VERSION 5.8 ;
BUSBITCHARS "[]" ;
DIVIDERCHAR "/" ;
UNITS
    DATABASE MICRONS 1000 ;
END UNITS

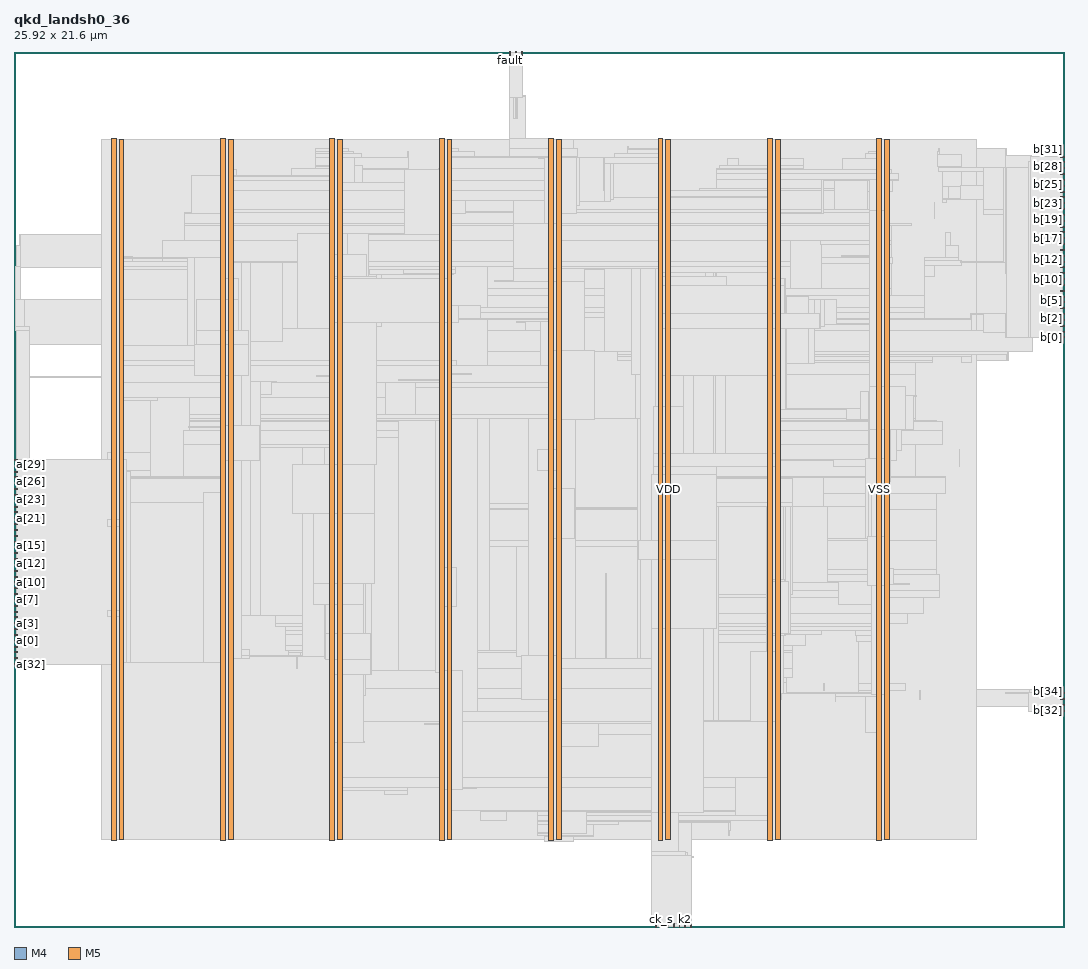
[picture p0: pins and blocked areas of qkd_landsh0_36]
MACRO qkd_landsh0_36
  FOREIGN qkd_landsh0_36 0 0 ;
  CLASS BLOCK ;
  SIZE 25.92 BY 21.6 ;
  PIN a[0]
    DIRECTION INPUT ;
    USE SIGNAL ;
    PORT
      LAYER M4 ;
        RECT  0 7.056 0.084 7.08 ;
    END
  END a[0]
  PIN a[10]
    DIRECTION INPUT ;
    USE SIGNAL ;
    PORT
      LAYER M4 ;
        RECT  0 8.496 0.084 8.52 ;
    END
  END a[10]
  PIN a[11]
    DIRECTION INPUT ;
    USE SIGNAL ;
    PORT
      LAYER M4 ;
        RECT  0 8.64 0.084 8.664 ;
    END
  END a[11]
  PIN a[12]
    DIRECTION INPUT ;
    USE SIGNAL ;
    PORT
      LAYER M4 ;
        RECT  0 8.784 0.084 8.808 ;
    END
  END a[12]
  PIN a[13]
    DIRECTION INPUT ;
    USE SIGNAL ;
    PORT
      LAYER M4 ;
        RECT  0 8.928 0.084 8.952 ;
    END
  END a[13]
  PIN a[14]
    DIRECTION INPUT ;
    USE SIGNAL ;
    PORT
      LAYER M4 ;
        RECT  0 9.072 0.084 9.096 ;
    END
  END a[14]
  PIN a[15]
    DIRECTION INPUT ;
    USE SIGNAL ;
    PORT
      LAYER M4 ;
        RECT  0 9.216 0.084 9.24 ;
    END
  END a[15]
  PIN a[16]
    DIRECTION INPUT ;
    USE SIGNAL ;
    PORT
      LAYER M4 ;
        RECT  0 9.36 0.084 9.384 ;
    END
  END a[16]
  PIN a[17]
    DIRECTION INPUT ;
    USE SIGNAL ;
    PORT
      LAYER M4 ;
        RECT  0 9.504 0.084 9.528 ;
    END
  END a[17]
  PIN a[18]
    DIRECTION INPUT ;
    USE SIGNAL ;
    PORT
      LAYER M4 ;
        RECT  0 9.648 0.084 9.672 ;
    END
  END a[18]
  PIN a[19]
    DIRECTION INPUT ;
    USE SIGNAL ;
    PORT
      LAYER M4 ;
        RECT  0 9.792 0.084 9.816 ;
    END
  END a[19]
  PIN a[1]
    DIRECTION INPUT ;
    USE SIGNAL ;
    PORT
      LAYER M4 ;
        RECT  0 7.2 0.084 7.224 ;
    END
  END a[1]
  PIN a[20]
    DIRECTION INPUT ;
    USE SIGNAL ;
    PORT
      LAYER M4 ;
        RECT  0 9.936 0.084 9.96 ;
    END
  END a[20]
  PIN a[21]
    DIRECTION INPUT ;
    USE SIGNAL ;
    PORT
      LAYER M4 ;
        RECT  0 10.08 0.084 10.104 ;
    END
  END a[21]
  PIN a[22]
    DIRECTION INPUT ;
    USE SIGNAL ;
    PORT
      LAYER M4 ;
        RECT  0 10.224 0.084 10.248 ;
    END
  END a[22]
  PIN a[23]
    DIRECTION INPUT ;
    USE SIGNAL ;
    PORT
      LAYER M4 ;
        RECT  0 10.368 0.084 10.392 ;
    END
  END a[23]
  PIN a[24]
    DIRECTION INPUT ;
    USE SIGNAL ;
    PORT
      LAYER M4 ;
        RECT  0 10.512 0.084 10.536 ;
    END
  END a[24]
  PIN a[25]
    DIRECTION INPUT ;
    USE SIGNAL ;
    PORT
      LAYER M4 ;
        RECT  0 10.656 0.084 10.68 ;
    END
  END a[25]
  PIN a[26]
    DIRECTION INPUT ;
    USE SIGNAL ;
    PORT
      LAYER M4 ;
        RECT  0 10.8 0.084 10.824 ;
    END
  END a[26]
  PIN a[27]
    DIRECTION INPUT ;
    USE SIGNAL ;
    PORT
      LAYER M4 ;
        RECT  0 10.944 0.084 10.968 ;
    END
  END a[27]
  PIN a[28]
    DIRECTION INPUT ;
    USE SIGNAL ;
    PORT
      LAYER M4 ;
        RECT  0 11.088 0.084 11.112 ;
    END
  END a[28]
  PIN a[29]
    DIRECTION INPUT ;
    USE SIGNAL ;
    PORT
      LAYER M4 ;
        RECT  0 11.232 0.084 11.256 ;
    END
  END a[29]
  PIN a[2]
    DIRECTION INPUT ;
    USE SIGNAL ;
    PORT
      LAYER M4 ;
        RECT  0 7.344 0.084 7.368 ;
    END
  END a[2]
  PIN a[30]
    DIRECTION INPUT ;
    USE SIGNAL ;
    PORT
      LAYER M4 ;
        RECT  0 11.376 0.084 11.4 ;
    END
  END a[30]
  PIN a[31]
    DIRECTION INPUT ;
    USE SIGNAL ;
    PORT
      LAYER M4 ;
        RECT  0 11.52 0.084 11.544 ;
    END
  END a[31]
  PIN a[32]
    DIRECTION INPUT ;
    USE SIGNAL ;
    PORT
      LAYER M4 ;
        RECT  0 6.48 0.084 6.504 ;
    END
  END a[32]
  PIN a[33]
    DIRECTION INPUT ;
    USE SIGNAL ;
    PORT
      LAYER M4 ;
        RECT  0 6.624 0.084 6.648 ;
    END
  END a[33]
  PIN a[34]
    DIRECTION INPUT ;
    USE SIGNAL ;
    PORT
      LAYER M4 ;
        RECT  0 6.768 0.084 6.792 ;
    END
  END a[34]
  PIN a[35]
    DIRECTION INPUT ;
    USE SIGNAL ;
    PORT
      LAYER M4 ;
        RECT  0 6.912 0.084 6.936 ;
    END
  END a[35]
  PIN a[3]
    DIRECTION INPUT ;
    USE SIGNAL ;
    PORT
      LAYER M4 ;
        RECT  0 7.488 0.084 7.512 ;
    END
  END a[3]
  PIN a[4]
    DIRECTION INPUT ;
    USE SIGNAL ;
    PORT
      LAYER M4 ;
        RECT  0 7.632 0.084 7.656 ;
    END
  END a[4]
  PIN a[5]
    DIRECTION INPUT ;
    USE SIGNAL ;
    PORT
      LAYER M4 ;
        RECT  0 7.776 0.084 7.8 ;
    END
  END a[5]
  PIN a[6]
    DIRECTION INPUT ;
    USE SIGNAL ;
    PORT
      LAYER M4 ;
        RECT  0 7.92 0.084 7.944 ;
    END
  END a[6]
  PIN a[7]
    DIRECTION INPUT ;
    USE SIGNAL ;
    PORT
      LAYER M4 ;
        RECT  0 8.064 0.084 8.088 ;
    END
  END a[7]
  PIN a[8]
    DIRECTION INPUT ;
    USE SIGNAL ;
    PORT
      LAYER M4 ;
        RECT  0 8.208 0.084 8.232 ;
    END
  END a[8]
  PIN a[9]
    DIRECTION INPUT ;
    USE SIGNAL ;
    PORT
      LAYER M4 ;
        RECT  0 8.352 0.084 8.376 ;
    END
  END a[9]
  PIN b[0]
    DIRECTION OUTPUT ;
    USE SIGNAL ;
    PORT
      LAYER M4 ;
        RECT  25.836 14.544 25.92 14.568 ;
    END
  END b[0]
  PIN b[10]
    DIRECTION OUTPUT ;
    USE SIGNAL ;
    PORT
      LAYER M4 ;
        RECT  25.836 15.984 25.92 16.008 ;
    END
  END b[10]
  PIN b[11]
    DIRECTION OUTPUT ;
    USE SIGNAL ;
    PORT
      LAYER M4 ;
        RECT  25.836 16.128 25.92 16.152 ;
    END
  END b[11]
  PIN b[12]
    DIRECTION OUTPUT ;
    USE SIGNAL ;
    PORT
      LAYER M4 ;
        RECT  25.836 16.272 25.92 16.296 ;
    END
  END b[12]
  PIN b[13]
    DIRECTION OUTPUT ;
    USE SIGNAL ;
    PORT
      LAYER M4 ;
        RECT  25.836 16.416 25.92 16.44 ;
    END
  END b[13]
  PIN b[14]
    DIRECTION OUTPUT ;
    USE SIGNAL ;
    PORT
      LAYER M4 ;
        RECT  25.836 16.56 25.92 16.584 ;
    END
  END b[14]
  PIN b[15]
    DIRECTION OUTPUT ;
    USE SIGNAL ;
    PORT
      LAYER M4 ;
        RECT  25.836 16.704 25.92 16.728 ;
    END
  END b[15]
  PIN b[16]
    DIRECTION OUTPUT ;
    USE SIGNAL ;
    PORT
      LAYER M4 ;
        RECT  25.836 16.848 25.92 16.872 ;
    END
  END b[16]
  PIN b[17]
    DIRECTION OUTPUT ;
    USE SIGNAL ;
    PORT
      LAYER M4 ;
        RECT  25.836 16.992 25.92 17.016 ;
    END
  END b[17]
  PIN b[18]
    DIRECTION OUTPUT ;
    USE SIGNAL ;
    PORT
      LAYER M4 ;
        RECT  25.836 17.136 25.92 17.16 ;
    END
  END b[18]
  PIN b[19]
    DIRECTION OUTPUT ;
    USE SIGNAL ;
    PORT
      LAYER M4 ;
        RECT  25.836 17.28 25.92 17.304 ;
    END
  END b[19]
  PIN b[1]
    DIRECTION OUTPUT ;
    USE SIGNAL ;
    PORT
      LAYER M4 ;
        RECT  25.836 14.688 25.92 14.712 ;
    END
  END b[1]
  PIN b[20]
    DIRECTION OUTPUT ;
    USE SIGNAL ;
    PORT
      LAYER M4 ;
        RECT  25.836 17.424 25.92 17.448 ;
    END
  END b[20]
  PIN b[21]
    DIRECTION OUTPUT ;
    USE SIGNAL ;
    PORT
      LAYER M4 ;
        RECT  25.836 17.568 25.92 17.592 ;
    END
  END b[21]
  PIN b[22]
    DIRECTION OUTPUT ;
    USE SIGNAL ;
    PORT
      LAYER M4 ;
        RECT  25.836 17.712 25.92 17.736 ;
    END
  END b[22]
  PIN b[23]
    DIRECTION OUTPUT ;
    USE SIGNAL ;
    PORT
      LAYER M4 ;
        RECT  25.836 17.856 25.92 17.88 ;
    END
  END b[23]
  PIN b[24]
    DIRECTION OUTPUT ;
    USE SIGNAL ;
    PORT
      LAYER M4 ;
        RECT  25.836 18 25.92 18.024 ;
    END
  END b[24]
  PIN b[25]
    DIRECTION OUTPUT ;
    USE SIGNAL ;
    PORT
      LAYER M4 ;
        RECT  25.836 18.144 25.92 18.168 ;
    END
  END b[25]
  PIN b[26]
    DIRECTION OUTPUT ;
    USE SIGNAL ;
    PORT
      LAYER M4 ;
        RECT  25.836 18.288 25.92 18.312 ;
    END
  END b[26]
  PIN b[27]
    DIRECTION OUTPUT ;
    USE SIGNAL ;
    PORT
      LAYER M4 ;
        RECT  25.836 18.432 25.92 18.456 ;
    END
  END b[27]
  PIN b[28]
    DIRECTION OUTPUT ;
    USE SIGNAL ;
    PORT
      LAYER M4 ;
        RECT  25.836 18.576 25.92 18.6 ;
    END
  END b[28]
  PIN b[29]
    DIRECTION OUTPUT ;
    USE SIGNAL ;
    PORT
      LAYER M4 ;
        RECT  25.836 18.72 25.92 18.744 ;
    END
  END b[29]
  PIN b[2]
    DIRECTION OUTPUT ;
    USE SIGNAL ;
    PORT
      LAYER M4 ;
        RECT  25.836 14.832 25.92 14.856 ;
    END
  END b[2]
  PIN b[30]
    DIRECTION OUTPUT ;
    USE SIGNAL ;
    PORT
      LAYER M4 ;
        RECT  25.836 18.864 25.92 18.888 ;
    END
  END b[30]
  PIN b[31]
    DIRECTION OUTPUT ;
    USE SIGNAL ;
    PORT
      LAYER M4 ;
        RECT  25.836 19.008 25.92 19.032 ;
    END
  END b[31]
  PIN b[32]
    DIRECTION OUTPUT ;
    USE SIGNAL ;
    PORT
      LAYER M4 ;
        RECT  25.836 5.328 25.92 5.352 ;
    END
  END b[32]
  PIN b[33]
    DIRECTION OUTPUT ;
    USE SIGNAL ;
    PORT
      LAYER M4 ;
        RECT  25.836 5.472 25.92 5.496 ;
    END
  END b[33]
  PIN b[34]
    DIRECTION OUTPUT ;
    USE SIGNAL ;
    PORT
      LAYER M4 ;
        RECT  25.836 5.616 25.92 5.64 ;
    END
  END b[34]
  PIN b[35]
    DIRECTION OUTPUT ;
    USE SIGNAL ;
    PORT
      LAYER M4 ;
        RECT  25.836 5.76 25.92 5.784 ;
    END
  END b[35]
  PIN b[3]
    DIRECTION OUTPUT ;
    USE SIGNAL ;
    PORT
      LAYER M4 ;
        RECT  25.836 14.976 25.92 15 ;
    END
  END b[3]
  PIN b[4]
    DIRECTION OUTPUT ;
    USE SIGNAL ;
    PORT
      LAYER M4 ;
        RECT  25.836 15.12 25.92 15.144 ;
    END
  END b[4]
  PIN b[5]
    DIRECTION OUTPUT ;
    USE SIGNAL ;
    PORT
      LAYER M4 ;
        RECT  25.836 15.264 25.92 15.288 ;
    END
  END b[5]
  PIN b[6]
    DIRECTION OUTPUT ;
    USE SIGNAL ;
    PORT
      LAYER M4 ;
        RECT  25.836 15.408 25.92 15.432 ;
    END
  END b[6]
  PIN b[7]
    DIRECTION OUTPUT ;
    USE SIGNAL ;
    PORT
      LAYER M4 ;
        RECT  25.836 15.552 25.92 15.576 ;
    END
  END b[7]
  PIN b[8]
    DIRECTION OUTPUT ;
    USE SIGNAL ;
    PORT
      LAYER M4 ;
        RECT  25.836 15.696 25.92 15.72 ;
    END
  END b[8]
  PIN b[9]
    DIRECTION OUTPUT ;
    USE SIGNAL ;
    PORT
      LAYER M4 ;
        RECT  25.836 15.84 25.92 15.864 ;
    END
  END b[9]
  PIN ck
    DIRECTION INPUT ;
    USE SIGNAL ;
    PORT
      LAYER M5 ;
        RECT  15.84 0 15.864 0.084 ;
    END
  END ck
  PIN ck_s
    DIRECTION INPUT ;
    USE SIGNAL ;
    PORT
      LAYER M5 ;
        RECT  15.984 0 16.008 0.084 ;
    END
  END ck_s
  PIN en
    DIRECTION INPUT ;
    USE SIGNAL ;
    PORT
      LAYER M5 ;
        RECT  16.128 0 16.152 0.084 ;
    END
  END en
  PIN fault
    DIRECTION OUTPUT ;
    USE SIGNAL ;
    PORT
      LAYER M5 ;
        RECT  12.24 21.516 12.264 21.6 ;
    END
  END fault
  PIN k0
    DIRECTION INPUT ;
    USE SIGNAL ;
    PORT
      LAYER M5 ;
        RECT  16.272 0 16.296 0.084 ;
    END
  END k0
  PIN k1
    DIRECTION INPUT ;
    USE SIGNAL ;
    PORT
      LAYER M5 ;
        RECT  16.416 0 16.44 0.084 ;
    END
  END k1
  PIN k2
    DIRECTION INPUT ;
    USE SIGNAL ;
    PORT
      LAYER M5 ;
        RECT  16.56 0 16.584 0.084 ;
    END
  END k2
  PIN rs
    DIRECTION INPUT ;
    USE SIGNAL ;
    PORT
      LAYER M5 ;
        RECT  16.704 0 16.728 0.084 ;
    END
  END rs
  PIN tie_hi
    DIRECTION OUTPUT ;
    USE SIGNAL ;
    PORT
      LAYER M5 ;
        RECT  12.384 21.516 12.408 21.6 ;
    END
  END tie_hi
  PIN tie_lo
    DIRECTION OUTPUT ;
    USE SIGNAL ;
    PORT
      LAYER M5 ;
        RECT  12.528 21.516 12.552 21.6 ;
    END
  END tie_lo
  PIN VDD
    DIRECTION INOUT ;
    USE POWER ;
    PORT
      LAYER M5 ;
        RECT  21.492 2.151 21.612 19.449 ;
        RECT  18.792 2.151 18.912 19.449 ;
        RECT  16.092 2.151 16.212 19.449 ;
        RECT  13.392 2.151 13.512 19.449 ;
        RECT  10.692 2.151 10.812 19.449 ;
        RECT  7.992 2.151 8.112 19.449 ;
        RECT  5.292 2.151 5.412 19.449 ;
        RECT  2.592 2.151 2.712 19.449 ;
    END
  END VDD
  PIN VSS
    DIRECTION INOUT ;
    USE GROUND ;
    PORT
      LAYER M5 ;
        RECT  21.3 2.137 21.42 19.463 ;
        RECT  18.6 2.137 18.72 19.463 ;
        RECT  15.9 2.137 16.02 19.463 ;
        RECT  13.2 2.137 13.32 19.463 ;
        RECT  10.5 2.137 10.62 19.463 ;
        RECT  7.8 2.137 7.92 19.463 ;
        RECT  5.1 2.137 5.22 19.463 ;
        RECT  2.4 2.137 2.52 19.463 ;
    END
  END VSS
  OBS
    LAYER RVTN ;
     RECT  2.16 2.16 23.76 2.295 ;
     RECT  2.16 2.565 23.76 2.835 ;
     RECT  2.16 3.105 23.76 3.375 ;
     RECT  2.16 3.645 23.76 3.915 ;
     RECT  2.16 4.185 23.76 4.455 ;
     RECT  2.16 4.725 23.76 4.995 ;
     RECT  2.16 5.265 23.76 5.535 ;
     RECT  2.16 5.805 23.76 6.075 ;
     RECT  2.16 6.345 23.76 6.615 ;
     RECT  2.16 6.885 23.76 7.155 ;
     RECT  2.16 7.425 23.76 7.695 ;
     RECT  2.16 7.965 23.76 8.235 ;
     RECT  2.16 8.505 23.76 8.775 ;
     RECT  2.16 9.045 23.76 9.315 ;
     RECT  2.16 9.585 23.76 9.855 ;
     RECT  2.16 10.125 23.76 10.395 ;
     RECT  2.16 10.665 23.76 10.935 ;
     RECT  2.16 11.205 23.76 11.475 ;
     RECT  2.16 11.745 23.76 12.015 ;
     RECT  2.16 12.285 23.76 12.555 ;
     RECT  2.16 12.825 23.76 13.095 ;
     RECT  2.16 13.365 23.76 13.635 ;
     RECT  2.16 13.905 23.76 14.175 ;
     RECT  2.16 14.445 23.76 14.715 ;
     RECT  2.16 14.985 23.76 15.255 ;
     RECT  2.16 15.525 23.76 15.795 ;
     RECT  2.16 16.065 23.76 16.335 ;
     RECT  2.16 16.605 23.76 16.875 ;
     RECT  2.16 17.145 23.76 17.415 ;
     RECT  2.16 17.685 23.76 17.955 ;
     RECT  2.16 18.225 23.76 18.495 ;
     RECT  2.16 18.765 23.76 19.035 ;
     RECT  2.16 19.305 23.76 19.44 ;
    LAYER RVTP ;
     RECT  2.16 2.295 23.76 2.565 ;
     RECT  2.16 2.835 23.76 3.105 ;
     RECT  2.16 3.375 23.76 3.645 ;
     RECT  2.16 3.915 23.76 4.185 ;
     RECT  2.16 4.455 23.76 4.725 ;
     RECT  2.16 4.995 23.76 5.265 ;
     RECT  2.16 5.535 23.76 5.805 ;
     RECT  2.16 6.075 23.76 6.345 ;
     RECT  2.16 6.615 23.76 6.885 ;
     RECT  2.16 7.155 23.76 7.425 ;
     RECT  2.16 7.695 23.76 7.965 ;
     RECT  2.16 8.235 23.76 8.505 ;
     RECT  2.16 8.775 23.76 9.045 ;
     RECT  2.16 9.315 23.76 9.585 ;
     RECT  2.16 9.855 23.76 10.125 ;
     RECT  2.16 10.395 23.76 10.665 ;
     RECT  2.16 10.935 23.76 11.205 ;
     RECT  2.16 11.475 23.76 11.745 ;
     RECT  2.16 12.015 23.76 12.285 ;
     RECT  2.16 12.555 23.76 12.825 ;
     RECT  2.16 13.095 23.76 13.365 ;
     RECT  2.16 13.635 23.76 13.905 ;
     RECT  2.16 14.175 23.76 14.445 ;
     RECT  2.16 14.715 23.76 14.985 ;
     RECT  2.16 15.255 23.76 15.525 ;
     RECT  2.16 15.795 23.76 16.065 ;
     RECT  2.16 16.335 23.76 16.605 ;
     RECT  2.16 16.875 23.76 17.145 ;
     RECT  2.16 17.415 23.76 17.685 ;
     RECT  2.16 17.955 23.76 18.225 ;
     RECT  2.16 18.495 23.76 18.765 ;
     RECT  2.16 19.035 23.76 19.305 ;
    LAYER M1 ;
     RECT  2.16 2.151 23.76 19.449 ;
    LAYER M2 ;
     RECT  0.031 16.272 0.067 16.29 ;
     RECT  0.031 14.724 0.103 14.742 ;
     RECT  0.103 14.382 0.139 14.742 ;
     RECT  0.067 16.272 0.139 16.83 ;
     RECT  0.139 14.382 0.175 14.814 ;
     RECT  0.175 14.382 0.247 14.94 ;
     RECT  0.067 10.404 0.275 10.422 ;
     RECT  0.535 6.696 2.16 6.714 ;
     RECT  0.139 8.982 2.16 9 ;
     RECT  2.011 11.25 2.16 11.268 ;
     RECT  0.211 13.572 2.16 13.59 ;
     RECT  0.247 14.382 2.16 15.48 ;
     RECT  0.139 16.272 2.16 17.1 ;
     RECT  2.16 2.151 13.099 19.449 ;
     RECT  13.099 2.106 13.811 19.449 ;
     RECT  13.811 2.151 23.76 19.449 ;
     RECT  23.76 13.986 24.503 19.224 ;
     RECT  24.503 13.986 24.539 18.954 ;
     RECT  23.76 5.436 25.079 5.868 ;
     RECT  24.539 14.22 25.079 18.954 ;
     RECT  25.079 14.22 25.115 15.084 ;
     RECT  25.079 16.506 25.115 18.864 ;
     RECT  25.115 14.22 25.151 14.238 ;
     RECT  25.079 5.544 25.835 5.868 ;
     RECT  25.115 16.506 25.835 17.982 ;
    LAYER M3 ;
     RECT  16.488 0.091 16.506 0.221 ;
     RECT  16.128 0.571 16.146 1.099 ;
     RECT  15.84 1.099 16.146 1.723 ;
     RECT  13.104 2.101 13.806 2.227 ;
     RECT  13.104 2.227 14.31 2.263 ;
     RECT  17.64 2.263 17.658 2.371 ;
     RECT  2.415 2.143 2.505 2.413 ;
     RECT  5.115 2.143 5.205 2.413 ;
     RECT  7.815 2.143 7.905 2.413 ;
     RECT  10.515 2.143 10.605 2.413 ;
     RECT  18.615 2.143 18.705 2.413 ;
     RECT  21.315 2.143 21.405 2.413 ;
     RECT  12.924 2.263 14.31 2.533 ;
     RECT  15.84 1.723 16.722 2.569 ;
     RECT  17.64 2.371 17.694 2.569 ;
     RECT  12.924 2.533 14.922 2.605 ;
     RECT  15.84 2.569 17.694 2.605 ;
     RECT  12.924 2.605 17.694 2.641 ;
     RECT  18.615 2.413 18.897 2.641 ;
     RECT  12.924 2.641 18.897 2.759 ;
     RECT  11.52 2.641 12.15 2.839 ;
     RECT  12.924 2.759 17.802 2.839 ;
     RECT  10.515 2.413 10.797 2.875 ;
     RECT  11.52 2.839 17.802 2.875 ;
     RECT  7.815 2.413 8.097 3.379 ;
     RECT  9.144 3.271 9.702 3.379 ;
     RECT  7.815 3.379 9.702 3.451 ;
     RECT  10.515 2.875 17.802 3.451 ;
     RECT  7.815 3.451 17.802 3.685 ;
     RECT  18.615 2.759 18.897 3.685 ;
     RECT  21.315 2.413 21.597 4.801 ;
     RECT  7.815 3.685 18.897 5.063 ;
     RECT  25.056 5.323 25.074 5.459 ;
     RECT  18.615 5.063 18.897 5.611 ;
     RECT  20.268 5.575 20.286 5.701 ;
     RECT  21.024 4.801 21.597 5.701 ;
     RECT  18.615 5.611 18.954 5.755 ;
     RECT  20.268 5.701 21.597 5.789 ;
     RECT  24.48 5.755 24.498 5.801 ;
     RECT  22.356 5.611 22.374 5.837 ;
     RECT  20.844 5.789 21.597 5.845 ;
     RECT  25.812 5.467 25.83 5.873 ;
     RECT  7.815 5.063 17.802 5.881 ;
     RECT  19.98 5.845 19.998 5.999 ;
     RECT  20.844 5.845 22.014 5.999 ;
     RECT  18.615 5.755 19.062 6.151 ;
     RECT  7.815 5.881 17.874 6.385 ;
     RECT  18.615 6.151 19.206 6.385 ;
     RECT  2.415 2.413 2.697 6.475 ;
     RECT  5.115 2.413 5.397 6.523 ;
     RECT  4.932 6.523 5.397 6.619 ;
     RECT  6.984 6.385 7.002 6.667 ;
     RECT  6.984 6.667 7.074 6.691 ;
     RECT  6.768 6.691 7.074 6.781 ;
     RECT  7.815 6.385 19.206 6.781 ;
     RECT  6.768 6.781 19.206 6.817 ;
     RECT  4.932 6.619 5.814 6.845 ;
     RECT  0.54 6.691 0.558 6.941 ;
     RECT  6.696 6.817 19.206 6.961 ;
     RECT  20.844 5.999 21.597 7.051 ;
     RECT  4.932 6.845 5.598 7.115 ;
     RECT  20.808 7.051 21.597 7.195 ;
     RECT  6.696 6.961 19.53 7.231 ;
     RECT  6.696 7.231 19.926 7.321 ;
     RECT  20.772 7.195 21.597 7.321 ;
     RECT  2.304 6.475 2.697 7.339 ;
     RECT  3.852 6.961 3.87 7.349 ;
     RECT  6.696 7.321 21.597 7.429 ;
     RECT  2.304 7.339 2.898 7.483 ;
     RECT  6.444 7.429 21.597 7.501 ;
     RECT  2.268 7.483 2.898 7.655 ;
     RECT  6.444 7.501 22.05 7.735 ;
     RECT  5.115 7.115 5.598 7.925 ;
     RECT  4.068 7.771 4.194 7.933 ;
     RECT  5.115 7.925 5.397 7.933 ;
     RECT  6.444 7.735 22.446 8.131 ;
     RECT  6.444 8.131 22.842 8.311 ;
     RECT  2.304 7.655 2.898 8.465 ;
     RECT  4.068 7.933 5.397 8.465 ;
     RECT  2.415 8.465 2.898 8.491 ;
     RECT  2.415 8.491 2.97 8.581 ;
     RECT  0.144 7.771 0.162 8.635 ;
     RECT  6.12 8.311 22.842 8.699 ;
     RECT  4.176 8.465 5.397 8.815 ;
     RECT  6.12 8.699 22.77 8.815 ;
     RECT  2.415 8.581 3.078 8.851 ;
     RECT  0.144 8.635 0.234 9.067 ;
     RECT  4.176 8.815 22.77 9.545 ;
     RECT  2.415 8.851 3.222 9.643 ;
     RECT  2.304 9.643 3.222 9.815 ;
     RECT  2.34 9.815 3.222 9.931 ;
     RECT  2.34 9.931 3.366 10.061 ;
     RECT  6.12 9.545 22.77 10.301 ;
     RECT  4.176 9.545 5.397 10.327 ;
     RECT  6.12 10.301 19.206 10.327 ;
     RECT  0.108 9.067 0.234 10.363 ;
     RECT  0.108 10.363 0.27 10.399 ;
     RECT  2.415 10.061 3.366 10.471 ;
     RECT  4.176 10.327 19.206 10.471 ;
     RECT  19.98 10.301 22.77 10.705 ;
     RECT  0.072 10.399 0.27 10.795 ;
     RECT  2.415 10.471 19.206 11.083 ;
     RECT  2.016 11.083 19.206 11.101 ;
     RECT  19.98 10.705 22.986 11.101 ;
     RECT  2.016 11.101 22.986 11.129 ;
     RECT  2.016 11.129 3.366 11.273 ;
     RECT  2.304 11.273 3.366 11.705 ;
     RECT  23.328 11.371 23.346 11.777 ;
     RECT  4.176 11.129 22.266 11.911 ;
     RECT  4.176 11.911 22.914 12.245 ;
     RECT  4.32 12.245 22.914 12.479 ;
     RECT  4.32 12.479 22.77 12.515 ;
     RECT  4.32 12.515 22.266 12.557 ;
     RECT  4.32 12.557 14.238 12.659 ;
     RECT  2.415 11.705 3.366 12.991 ;
     RECT  2.415 12.991 3.546 13.063 ;
     RECT  4.32 12.659 9.162 13.063 ;
     RECT  9.9 12.659 14.238 13.325 ;
     RECT  2.415 13.063 9.162 13.441 ;
     RECT  9.9 13.325 14.022 13.441 ;
     RECT  15.336 12.557 22.266 13.627 ;
     RECT  2.415 13.441 14.022 13.865 ;
     RECT  15.264 13.627 22.266 13.945 ;
     RECT  2.415 13.865 10.926 13.973 ;
     RECT  15.264 13.945 22.662 13.981 ;
     RECT  14.904 13.981 22.662 14.071 ;
     RECT  23.4 13.945 23.634 14.071 ;
     RECT  14.904 14.071 23.634 14.143 ;
     RECT  24.516 13.981 24.534 14.143 ;
     RECT  11.7 13.865 14.022 14.203 ;
     RECT  14.904 14.143 24.534 14.203 ;
     RECT  11.7 14.203 24.534 14.215 ;
     RECT  11.7 14.215 25.146 14.717 ;
     RECT  0.072 10.795 0.378 14.719 ;
     RECT  0.036 14.719 0.378 14.819 ;
     RECT  2.415 13.973 10.797 14.917 ;
     RECT  2.415 14.917 10.962 14.989 ;
     RECT  11.7 14.717 23.634 14.989 ;
     RECT  2.415 14.989 23.634 15.017 ;
     RECT  23.616 15.017 23.634 15.149 ;
     RECT  2.415 15.017 22.482 15.179 ;
     RECT  9.648 15.179 22.482 15.287 ;
     RECT  24.516 14.717 25.146 15.293 ;
     RECT  9.648 15.287 10.926 15.341 ;
     RECT  0.036 14.819 0.27 15.485 ;
     RECT  11.7 15.287 22.482 15.593 ;
     RECT  11.7 15.593 21.654 15.755 ;
     RECT  24.516 15.293 25.11 15.872 ;
     RECT  9.648 15.341 10.797 15.961 ;
     RECT  22.464 15.593 22.482 16.069 ;
     RECT  9.612 15.961 10.797 16.105 ;
     RECT  24.516 15.872 25.074 16.123 ;
     RECT  9.612 16.105 10.854 16.141 ;
     RECT  2.415 15.179 8.766 16.231 ;
     RECT  9.612 16.141 10.89 16.231 ;
     RECT  0.036 15.485 0.162 16.295 ;
     RECT  2.415 16.231 10.89 16.303 ;
     RECT  11.7 15.755 19.17 16.303 ;
     RECT  22.464 16.069 22.734 16.339 ;
     RECT  19.944 15.755 21.654 16.375 ;
     RECT  2.415 16.303 19.17 16.439 ;
     RECT  22.464 16.339 23.382 16.445 ;
     RECT  19.944 16.375 21.69 16.529 ;
     RECT  22.464 16.445 23.31 16.529 ;
     RECT  2.415 16.439 2.934 16.541 ;
     RECT  24.48 16.123 25.074 16.799 ;
     RECT  0.072 16.295 0.162 16.835 ;
     RECT  23.004 16.529 23.31 16.835 ;
     RECT  19.944 16.529 21.654 16.843 ;
     RECT  3.672 16.439 19.17 16.943 ;
     RECT  4.212 16.943 19.17 16.951 ;
     RECT  19.908 16.843 21.654 16.951 ;
     RECT  24.48 16.799 24.498 16.951 ;
     RECT  0.144 16.835 0.162 17.105 ;
     RECT  23.004 16.835 23.13 17.141 ;
     RECT  4.212 16.951 21.654 17.311 ;
     RECT  4.212 17.311 22.158 17.375 ;
     RECT  24.444 16.951 24.498 17.563 ;
     RECT  24.444 17.563 25.074 17.581 ;
     RECT  4.212 17.375 21.597 17.645 ;
     RECT  4.572 17.645 21.597 17.717 ;
     RECT  23.94 17.581 25.074 17.741 ;
     RECT  22.716 17.491 22.734 17.879 ;
     RECT  22.932 17.887 23.022 17.959 ;
     RECT  25.812 16.501 25.83 17.987 ;
     RECT  21.06 17.717 21.597 18.157 ;
     RECT  4.572 17.717 20.25 18.185 ;
     RECT  16.92 18.185 20.25 18.221 ;
     RECT  24.444 17.741 25.074 18.229 ;
     RECT  22.932 17.959 23.058 18.283 ;
     RECT  4.572 18.185 16.197 18.419 ;
     RECT  21.06 18.157 21.69 18.427 ;
     RECT  17.352 18.221 20.25 18.463 ;
     RECT  21.06 18.427 21.834 18.463 ;
     RECT  4.572 18.419 9.738 18.523 ;
     RECT  4.392 18.523 9.738 18.563 ;
     RECT  17.352 18.463 21.834 18.599 ;
     RECT  22.932 18.283 23.382 18.661 ;
     RECT  24.444 18.229 25.11 18.661 ;
     RECT  5.115 18.563 5.49 18.689 ;
     RECT  17.352 18.599 21.654 18.689 ;
     RECT  6.84 18.563 9.738 18.725 ;
     RECT  10.476 18.419 16.197 18.725 ;
     RECT  17.352 18.689 19.494 18.725 ;
     RECT  22.824 18.661 25.11 18.749 ;
     RECT  22.824 18.749 23.382 18.769 ;
     RECT  17.424 18.725 19.494 18.797 ;
     RECT  17.604 18.797 17.874 18.959 ;
     RECT  18.615 18.797 19.494 18.959 ;
     RECT  20.448 18.689 21.597 18.959 ;
     RECT  7.452 18.725 9.738 18.995 ;
     RECT  10.515 18.725 16.197 18.995 ;
     RECT  10.515 18.995 13.914 19.031 ;
     RECT  24.48 18.749 25.11 19.037 ;
     RECT  22.788 18.769 23.382 19.067 ;
     RECT  7.452 18.995 8.586 19.103 ;
     RECT  14.832 18.995 16.197 19.103 ;
     RECT  21.024 18.959 21.597 19.103 ;
     RECT  7.452 19.103 8.37 19.139 ;
     RECT  9.72 18.995 9.738 19.139 ;
     RECT  10.515 19.031 11.358 19.139 ;
     RECT  21.096 19.103 21.597 19.139 ;
     RECT  22.788 19.067 22.842 19.139 ;
     RECT  2.415 16.541 2.697 19.187 ;
     RECT  5.115 18.689 5.397 19.187 ;
     RECT  15.156 19.103 16.197 19.187 ;
     RECT  18.615 18.959 18.897 19.187 ;
     RECT  21.315 19.139 21.597 19.187 ;
     RECT  7.452 19.139 8.262 19.229 ;
     RECT  10.515 19.139 10.962 19.229 ;
     RECT  12.24 19.031 13.914 19.229 ;
     RECT  15.156 19.187 16.074 19.229 ;
     RECT  22.824 19.139 22.842 19.229 ;
     RECT  24.48 19.037 24.498 19.229 ;
     RECT  15.156 19.229 15.174 19.265 ;
     RECT  2.415 19.187 2.505 19.457 ;
     RECT  5.115 19.187 5.205 19.457 ;
     RECT  7.815 19.229 7.905 19.457 ;
     RECT  10.515 19.229 10.605 19.457 ;
     RECT  12.24 19.229 13.305 19.457 ;
     RECT  15.915 19.229 16.005 19.457 ;
     RECT  18.615 19.187 18.705 19.457 ;
     RECT  21.315 19.187 21.405 19.457 ;
     RECT  12.24 19.457 12.618 20.525 ;
    LAYER M4 ;
     RECT  0.06 6.48 2.408 11.544 ;
     RECT  2.408 2.148 2.512 19.452 ;
     RECT  2.512 2.418 2.704 19.182 ;
     RECT  2.704 6.528 2.765 11.544 ;
     RECT  2.765 6.528 2.873 11.256 ;
     RECT  2.704 14.352 4.273 15.48 ;
     RECT  2.704 16.512 4.273 16.536 ;
     RECT  4.201 17.616 4.381 17.64 ;
     RECT  4.273 14.352 4.453 16.536 ;
     RECT  2.873 6.528 4.669 10.488 ;
     RECT  4.669 6.528 5.108 10.728 ;
     RECT  4.309 12.336 5.108 12.36 ;
     RECT  4.453 13.632 5.108 16.536 ;
     RECT  4.381 17.616 5.108 18.552 ;
     RECT  5.108 2.148 5.212 19.452 ;
     RECT  5.212 2.418 5.404 19.182 ;
     RECT  5.404 6.624 5.609 16.392 ;
     RECT  5.609 6.624 5.825 6.696 ;
     RECT  5.609 7.68 5.836 16.392 ;
     RECT  5.836 7.68 6.083 13.464 ;
     RECT  5.404 18.528 6.149 18.552 ;
     RECT  6.083 13.152 6.365 13.464 ;
     RECT  6.365 13.44 6.473 13.464 ;
     RECT  5.836 14.448 6.617 16.392 ;
     RECT  6.617 14.784 7.009 16.392 ;
     RECT  5.825 6.672 7.117 6.696 ;
     RECT  6.083 7.68 7.117 11.832 ;
     RECT  7.117 6.672 7.669 11.832 ;
     RECT  7.669 6.624 7.808 11.832 ;
     RECT  7.477 13.584 7.808 13.608 ;
     RECT  7.009 14.784 7.808 17.112 ;
     RECT  7.441 18.768 7.808 18.792 ;
     RECT  7.808 2.148 7.912 19.452 ;
     RECT  7.912 2.418 8.104 19.182 ;
     RECT  8.104 13.584 8.243 17.112 ;
     RECT  8.104 18.384 8.417 18.984 ;
     RECT  8.104 4.56 8.525 12.552 ;
     RECT  8.417 18.384 8.597 18.792 ;
     RECT  8.525 4.56 8.627 12.072 ;
     RECT  8.627 4.56 8.661 4.584 ;
     RECT  8.627 5.712 8.668 12.072 ;
     RECT  8.243 14.448 8.749 17.112 ;
     RECT  8.668 6.24 8.821 12.072 ;
     RECT  8.749 14.448 8.957 16.104 ;
     RECT  8.957 14.832 9.065 16.104 ;
     RECT  8.821 6.336 9.493 12.072 ;
     RECT  8.749 17.088 9.637 17.112 ;
     RECT  8.597 18.384 9.637 18.696 ;
     RECT  9.493 6.336 10.393 12.504 ;
     RECT  10.141 4.992 10.508 5.016 ;
     RECT  10.393 6.288 10.508 12.504 ;
     RECT  9.493 13.488 10.508 13.512 ;
     RECT  9.065 14.928 10.508 16.104 ;
     RECT  9.637 17.088 10.508 18.696 ;
     RECT  10.508 2.148 10.612 19.452 ;
     RECT  10.612 2.418 10.804 19.182 ;
     RECT  10.804 14.928 10.973 15.336 ;
     RECT  10.804 3.408 11.075 4.152 ;
     RECT  10.804 17.616 11.153 17.928 ;
     RECT  10.804 13.632 11.297 13.656 ;
     RECT  11.075 3.408 11.405 3.432 ;
     RECT  10.804 5.328 11.441 12.552 ;
     RECT  10.973 15.024 11.513 15.336 ;
     RECT  11.441 6.816 11.729 12.552 ;
     RECT  11.869 15.936 12.325 15.96 ;
     RECT  11.153 17.664 12.325 17.928 ;
     RECT  12.229 20.496 12.332 20.52 ;
     RECT  11.729 6.816 12.409 9.384 ;
     RECT  12.332 19.968 12.419 20.52 ;
     RECT  12.409 14.928 12.625 14.952 ;
     RECT  12.419 20.496 12.629 20.52 ;
     RECT  12.409 6.672 12.697 9.384 ;
     RECT  11.729 10.464 12.697 12.552 ;
     RECT  12.625 14.736 12.985 14.952 ;
     RECT  12.325 15.936 13.093 17.928 ;
     RECT  12.949 18.96 13.093 18.984 ;
     RECT  12.913 2.304 13.208 2.328 ;
     RECT  11.441 5.328 13.208 5.64 ;
     RECT  12.697 6.672 13.208 12.552 ;
     RECT  12.985 13.872 13.208 14.952 ;
     RECT  13.093 15.936 13.208 18.984 ;
     RECT  13.208 2.148 13.312 19.452 ;
     RECT  13.312 2.304 13.504 19.182 ;
     RECT  13.504 16.08 13.529 16.248 ;
     RECT  13.504 13.536 13.637 15.048 ;
     RECT  13.504 6.624 13.859 12.552 ;
     RECT  13.504 17.616 13.889 18.984 ;
     RECT  13.889 17.808 13.961 18.984 ;
     RECT  13.504 2.304 14.141 2.856 ;
     RECT  13.504 4.464 14.429 5.016 ;
     RECT  13.637 14.208 14.569 15.048 ;
     RECT  13.529 16.224 14.569 16.248 ;
     RECT  13.961 17.904 14.579 18.984 ;
     RECT  14.579 17.904 14.717 18.84 ;
     RECT  14.717 17.952 14.789 18.84 ;
     RECT  14.569 14.208 15.253 16.248 ;
     RECT  13.859 6.624 15.397 9.384 ;
     RECT  13.859 10.368 15.397 12.552 ;
     RECT  15.397 6.624 15.469 12.552 ;
     RECT  15.253 13.632 15.469 16.248 ;
     RECT  15.469 6.624 15.829 16.248 ;
     RECT  14.141 2.832 15.908 2.856 ;
     RECT  14.429 4.752 15.908 5.016 ;
     RECT  15.829 6.336 15.908 16.248 ;
     RECT  14.789 18 15.908 18.84 ;
     RECT  15.733 0.096 15.973 0.12 ;
     RECT  15.829 1.104 15.973 1.128 ;
     RECT  15.908 2.148 16.012 19.452 ;
     RECT  16.012 2.148 16.204 19.182 ;
     RECT  15.973 0.096 16.225 1.128 ;
     RECT  16.225 0.096 16.307 1.848 ;
     RECT  16.307 0.096 16.403 0.264 ;
     RECT  16.403 0.096 16.517 0.216 ;
     RECT  16.517 0.192 16.54 0.216 ;
     RECT  16.307 1.728 16.625 1.848 ;
     RECT  16.204 4.992 16.769 16.152 ;
     RECT  16.625 1.728 16.777 1.752 ;
     RECT  16.204 2.832 17.027 2.856 ;
     RECT  16.769 5.088 17.273 16.152 ;
     RECT  17.273 11.376 17.315 16.152 ;
     RECT  17.315 14.832 17.353 16.152 ;
     RECT  17.273 5.088 17.389 10.392 ;
     RECT  17.389 5.088 18.565 7.032 ;
     RECT  17.389 8.208 18.565 10.392 ;
     RECT  18.565 5.088 18.608 10.392 ;
     RECT  17.315 11.376 18.608 13.848 ;
     RECT  17.353 15.552 18.608 16.152 ;
     RECT  16.204 18 18.608 18.024 ;
     RECT  18.608 2.148 18.712 19.452 ;
     RECT  18.712 2.418 18.904 19.182 ;
     RECT  18.904 5.76 19.001 10.392 ;
     RECT  19.001 7.2 19.043 10.392 ;
     RECT  18.904 12.768 19.043 16.008 ;
     RECT  19.001 5.76 19.073 6.024 ;
     RECT  19.043 12.768 19.073 15.576 ;
     RECT  19.043 7.248 19.18 10.392 ;
     RECT  19.18 8.208 19.217 10.392 ;
     RECT  19.073 13.92 19.613 15.576 ;
     RECT  19.613 13.92 19.757 15.48 ;
     RECT  19.757 14.784 19.907 15.48 ;
     RECT  18.904 17.616 19.933 17.64 ;
     RECT  19.933 17.616 19.973 18.456 ;
     RECT  19.907 14.832 20.009 15.48 ;
     RECT  19.217 8.496 20.081 10.392 ;
     RECT  18.904 11.52 20.221 11.544 ;
     RECT  20.009 14.88 20.297 15.48 ;
     RECT  20.081 8.496 20.365 8.52 ;
     RECT  19.073 12.768 20.545 12.792 ;
     RECT  20.545 12.528 20.905 12.792 ;
     RECT  20.081 9.6 21.013 10.392 ;
     RECT  20.221 11.376 21.013 11.544 ;
     RECT  21.013 9.6 21.085 11.544 ;
     RECT  20.905 12.528 21.085 13.224 ;
     RECT  19.973 18.432 21.109 18.456 ;
     RECT  20.365 7.968 21.157 8.52 ;
     RECT  21.085 9.6 21.157 13.224 ;
     RECT  20.297 14.88 21.157 14.904 ;
     RECT  19.073 5.76 21.308 5.784 ;
     RECT  21.157 7.968 21.308 13.224 ;
     RECT  21.157 14.256 21.308 14.904 ;
     RECT  20.437 16.56 21.308 16.584 ;
     RECT  21.109 17.664 21.308 18.456 ;
     RECT  21.308 2.148 21.412 19.452 ;
     RECT  21.412 2.418 21.604 19.182 ;
     RECT  21.604 10.992 21.629 13.32 ;
     RECT  21.604 8.448 21.701 8.856 ;
     RECT  21.629 11.52 21.773 13.32 ;
     RECT  21.773 11.76 21.917 13.32 ;
     RECT  21.917 12.288 22.019 13.32 ;
     RECT  21.701 8.448 22.097 8.472 ;
     RECT  22.019 12.288 22.205 13.128 ;
     RECT  22.205 13.104 22.277 13.128 ;
     RECT  22.921 17.952 23.353 17.976 ;
     RECT  23.605 15.12 23.929 15.144 ;
     RECT  23.353 17.952 23.929 18.312 ;
     RECT  23.353 16.416 24.433 16.44 ;
     RECT  23.929 17.712 24.433 18.744 ;
     RECT  23.929 14.688 24.469 15.144 ;
     RECT  24.433 16.416 24.469 18.744 ;
     RECT  24.469 14.544 24.505 15.144 ;
     RECT  24.469 16.128 24.505 18.744 ;
     RECT  24.469 5.76 25.045 5.784 ;
     RECT  24.505 14.544 25.045 18.744 ;
     RECT  25.045 14.544 25.081 18.888 ;
     RECT  25.045 5.328 25.884 5.784 ;
     RECT  25.081 14.544 25.884 19.032 ;
    LAYER M5 ;
     RECT  15.84 0.016 16.728 0.085 ;
     RECT  15.744 0.085 16.728 1.763 ;
     RECT  15.744 1.763 16.584 1.859 ;
     RECT  2.4 2.137 2.52 2.151 ;
     RECT  5.1 2.137 5.22 2.151 ;
     RECT  7.8 2.137 7.92 2.151 ;
     RECT  10.5 2.137 10.62 2.151 ;
     RECT  13.2 2.137 13.32 2.151 ;
     RECT  18.6 2.137 18.72 2.151 ;
     RECT  21.3 2.137 21.42 2.151 ;
     RECT  15.744 1.859 16.392 2.821 ;
     RECT  10.5 2.151 10.812 3.397 ;
     RECT  7.8 2.151 8.112 4.549 ;
     RECT  18.6 2.151 18.912 5.077 ;
     RECT  13.2 2.151 13.512 5.605 ;
     RECT  21.3 2.151 21.612 5.749 ;
     RECT  7.8 4.549 8.616 6.229 ;
     RECT  10.5 3.397 11.064 6.323 ;
     RECT  7.8 6.229 8.808 6.613 ;
     RECT  12.528 5.605 13.512 6.707 ;
     RECT  18.192 5.077 18.912 6.803 ;
     RECT  18.6 6.803 18.912 7.189 ;
     RECT  7.68 6.613 8.808 7.235 ;
     RECT  18.6 7.189 19.032 7.237 ;
     RECT  15.744 2.821 17.016 7.381 ;
     RECT  2.4 2.151 2.712 7.669 ;
     RECT  2.304 7.669 2.712 7.811 ;
     RECT  10.5 6.323 10.812 7.909 ;
     RECT  7.68 7.235 8.616 7.957 ;
     RECT  21.168 5.749 21.612 8.437 ;
     RECT  7.392 7.957 8.616 8.485 ;
     RECT  18.6 7.237 19.128 8.531 ;
     RECT  18.6 8.531 19.032 8.579 ;
     RECT  14.592 6.661 14.616 8.723 ;
     RECT  10.5 7.909 10.92 8.867 ;
     RECT  15.744 7.381 17.352 9.061 ;
     RECT  15.408 9.061 17.352 9.539 ;
     RECT  13.2 6.707 13.512 9.589 ;
     RECT  21.072 8.437 21.612 9.635 ;
     RECT  2.4 7.811 2.712 9.877 ;
     RECT  2.304 9.877 2.712 10.067 ;
     RECT  7.392 8.485 8.904 10.213 ;
     RECT  13.2 9.589 13.848 10.835 ;
     RECT  21.168 9.635 21.612 10.885 ;
     RECT  15.744 9.539 17.352 11.171 ;
     RECT  13.2 10.835 13.512 11.269 ;
     RECT  15.792 11.171 17.352 11.365 ;
     RECT  18.6 8.579 18.912 11.365 ;
     RECT  6.864 10.213 8.904 11.411 ;
     RECT  7.8 11.411 8.904 11.413 ;
     RECT  5.1 2.151 5.412 11.509 ;
     RECT  21.024 10.885 21.612 11.555 ;
     RECT  15.792 11.365 18.912 11.699 ;
     RECT  12.912 11.269 13.512 11.795 ;
     RECT  21.12 11.555 21.612 12.277 ;
     RECT  5.1 11.509 6.072 12.371 ;
     RECT  13.2 11.795 13.512 12.517 ;
     RECT  15.792 11.699 16.536 12.851 ;
     RECT  21.12 12.277 22.008 13.331 ;
     RECT  5.1 12.371 5.412 13.621 ;
     RECT  15.9 12.851 16.536 13.621 ;
     RECT  17.568 11.699 18.912 13.621 ;
     RECT  13.2 12.517 14.328 14.243 ;
     RECT  4.464 13.621 5.784 14.387 ;
     RECT  4.512 14.387 5.784 14.723 ;
     RECT  15.9 13.621 18.912 14.773 ;
     RECT  7.8 11.413 8.952 14.917 ;
     RECT  10.5 8.867 10.812 14.917 ;
     RECT  15.9 14.773 19.896 15.155 ;
     RECT  4.512 14.723 5.544 15.491 ;
     RECT  15.9 15.155 19.032 15.827 ;
     RECT  13.2 14.243 14.088 15.925 ;
     RECT  5.1 15.491 5.544 16.019 ;
     RECT  7.8 14.917 10.812 16.019 ;
     RECT  18.6 15.827 19.032 16.019 ;
     RECT  7.8 16.019 8.952 16.067 ;
     RECT  15.9 15.827 17.592 16.067 ;
     RECT  15.9 16.067 17.064 16.163 ;
     RECT  12.336 15.925 14.088 16.259 ;
     RECT  7.8 16.067 8.712 16.595 ;
     RECT  12.336 16.259 13.512 17.363 ;
     RECT  21.12 13.331 21.612 17.699 ;
     RECT  14.544 18.181 14.568 18.995 ;
     RECT  2.4 10.067 2.712 19.449 ;
     RECT  5.1 16.019 5.412 19.449 ;
     RECT  7.8 16.595 8.112 19.449 ;
     RECT  10.5 16.019 10.812 19.449 ;
     RECT  13.2 17.363 13.512 19.449 ;
     RECT  15.9 16.163 16.212 19.449 ;
     RECT  18.6 16.019 18.912 19.449 ;
     RECT  21.3 17.699 21.612 19.449 ;
     RECT  2.4 19.449 2.52 19.463 ;
     RECT  5.1 19.449 5.22 19.463 ;
     RECT  7.8 19.449 7.92 19.463 ;
     RECT  10.5 19.449 10.62 19.463 ;
     RECT  13.2 19.449 13.32 19.463 ;
     RECT  15.9 19.449 16.02 19.463 ;
     RECT  18.6 19.449 18.72 19.463 ;
     RECT  21.3 19.449 21.42 19.463 ;
     RECT  12.384 19.957 12.408 20.485 ;
     RECT  12.24 20.485 12.552 21.584 ;
  END
END qkd_landsh0_36
END LIBRARY
